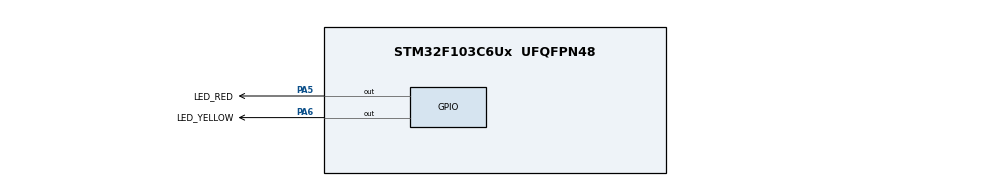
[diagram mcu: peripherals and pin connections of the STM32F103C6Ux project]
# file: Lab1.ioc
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Mcu.Family=STM32F1
Mcu.Name=STM32F103C6Ux
Mcu.Package=UFQFPN48
NVIC.PriorityGroup=NVIC_PRIORITYGROUP_4
PA5.GPIO_Label=LED_RED
PA5.Signal=GPIO_Output
PA6.GPIO_Label=LED_YELLOW
PA6.Signal=GPIO_Output
ProjectManager.HeapSize=0x200
ProjectManager.StackSize=0x400
ProjectManager.TargetToolchain=STM32CubeIDE
RCC.APB1Freq_Value=8000000
RCC.APB2Freq_Value=8000000
VP_SYS_VS_ND.Mode=No_Debug
board=custom

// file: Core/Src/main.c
/* USER CODE BEGIN Header */
/**
  ******************************************************************************
  * @file           : main.c
  * @brief          : Main program body
  ******************************************************************************
  * @attention
  *
  * <h2><center>&copy; Copyright (c) 2023 STMicroelectronics.
  * All rights reserved.</center></h2>
  *
  * This software component is licensed by ST under BSD 3-Clause license,
  * the "License"; You may not use this file except in compliance with the
  * License. You may obtain a copy of the License at:
  *                        opensource.org/licenses/BSD-3-Clause
  *
  ******************************************************************************
  */
/* USER CODE END Header */
#include "main.h"

void SystemClock_Config(void);
static void MX_GPIO_Init(void);

/* USER CODE BEGIN 0 */
void setNumberOnClock(int num){
	switch(num){
	case 0:
		HAL_GPIO_WritePin(LED_0_GPIO_Port, LED_0_Pin, RESET);
	  	break;
	case 1:
		HAL_GPIO_WritePin(LED_1_GPIO_Port, LED_1_Pin, RESET);
		break;
	case 2:
		HAL_GPIO_WritePin(LED_2_GPIO_Port, LED_2_Pin, RESET);
		break;
	case 3:
		HAL_GPIO_WritePin(LED_3_GPIO_Port, LED_3_Pin, RESET);
		break;
	case 4:
		HAL_GPIO_WritePin(LED_4_GPIO_Port, LED_4_Pin, RESET);
		break;
	case 5:
		HAL_GPIO_WritePin(LED_5_GPIO_Port, LED_5_Pin, RESET);
		break;
	case 6:
		HAL_GPIO_WritePin(LED_6_GPIO_Port, LED_6_Pin, RESET);
		break;
	case 7:
		HAL_GPIO_WritePin(LED_7_GPIO_Port, LED_7_Pin, RESET);
		break;
	case 8:
		HAL_GPIO_WritePin(LED_8_GPIO_Port, LED_8_Pin, RESET);
		break;
	case 9:
		HAL_GPIO_WritePin(LED_9_GPIO_Port, LED_9_Pin, RESET);
		break;
	case 10:
		HAL_GPIO_WritePin(LED_10_GPIO_Port, LED_10_Pin, RESET);
		break;
	case 11:
		HAL_GPIO_WritePin(LED_11_GPIO_Port, LED_11_Pin, RESET);
		break;
	default:
		break;

	}
}

void clearAllClock (){
	HAL_GPIO_WritePin(LED_0_GPIO_Port, LED_0_Pin, SET);
	HAL_GPIO_WritePin(LED_1_GPIO_Port, LED_1_Pin, SET);
	HAL_GPIO_WritePin(LED_2_GPIO_Port, LED_2_Pin, SET);
	HAL_GPIO_WritePin(LED_3_GPIO_Port, LED_3_Pin, SET);
	HAL_GPIO_WritePin(LED_4_GPIO_Port, LED_4_Pin, SET);
	HAL_GPIO_WritePin(LED_5_GPIO_Port, LED_5_Pin, SET);
	HAL_GPIO_WritePin(LED_6_GPIO_Port, LED_6_Pin, SET);
	HAL_GPIO_WritePin(LED_7_GPIO_Port, LED_7_Pin, SET);
	HAL_GPIO_WritePin(LED_8_GPIO_Port, LED_8_Pin, SET);
	HAL_GPIO_WritePin(LED_9_GPIO_Port, LED_9_Pin, SET);
	HAL_GPIO_WritePin(LED_10_GPIO_Port, LED_10_Pin, SET);
	HAL_GPIO_WritePin(LED_11_GPIO_Port, LED_11_Pin, SET);
}

void clearNumberOnClock(int num){
	switch(num){
	case 0:
		HAL_GPIO_WritePin(LED_0_GPIO_Port, LED_0_Pin, SET);
		break;
	case 1:
		HAL_GPIO_WritePin(LED_1_GPIO_Port, LED_1_Pin, SET);
		break;
	case 2:
		HAL_GPIO_WritePin(LED_2_GPIO_Port, LED_2_Pin, SET);
		break;
	case 3:
		HAL_GPIO_WritePin(LED_3_GPIO_Port, LED_3_Pin, SET);
		break;
	case 4:
		HAL_GPIO_WritePin(LED_4_GPIO_Port, LED_4_Pin, SET);
		break;
	case 5:
		HAL_GPIO_WritePin(LED_5_GPIO_Port, LED_5_Pin, SET);
		break;
	case 6:
		HAL_GPIO_WritePin(LED_6_GPIO_Port, LED_6_Pin, SET);
		break;
	case 7:
		HAL_GPIO_WritePin(LED_7_GPIO_Port, LED_7_Pin, SET);
		break;
	case 8:
		HAL_GPIO_WritePin(LED_8_GPIO_Port, LED_8_Pin, SET);
		break;
	case 9:
		HAL_GPIO_WritePin(LED_9_GPIO_Port, LED_9_Pin, SET);
		break;
	case 10:
		HAL_GPIO_WritePin(LED_10_GPIO_Port, LED_10_Pin, SET);
		break;
	case 11:
		HAL_GPIO_WritePin(LED_11_GPIO_Port, LED_11_Pin, SET);
		break;
	default:
		break;
	}
}

const int HOUR = 12;
const int MINUTE = 60;
const int SECOND = 60;
/* USER CODE END 0 */

int main(void)
{

  /* MCU Configuration--------------------------------------------------------*/

  /* Reset of all peripherals, Initializes the Flash interface and the Systick. */
  HAL_Init();

  /* Configure the system clock */
  SystemClock_Config();

  /* Initialize all configured peripherals */
  MX_GPIO_Init();

  /* Infinite loop */
  /* USER CODE BEGIN WHILE */
  int sec = 0;
  int min = 0;
  int hour = 0;

  while (1)
  {
	  clearAllClock();
	  if (sec >= SECOND){
		  min++;
		  sec = 0;
	  }

	  if (min >= MINUTE) {
		  hour++;
		  min = 0;
	  }

	  if (hour >= HOUR){
		  hour = 0;
	  }
	  setNumberOnClock(hour);
	  setNumberOnClock(min/5);
	  setNumberOnClock(sec/5);
	  sec++;

	  HAL_Delay(1000);
    /* USER CODE END WHILE */

  }
}

void SystemClock_Config(void)
{
  RCC_OscInitTypeDef RCC_OscInitStruct = {0};
  RCC_ClkInitTypeDef RCC_ClkInitStruct = {0};

  /** Initializes the RCC Oscillators according to the specified parameters
  * in the RCC_OscInitTypeDef structure.
  */
  RCC_OscInitStruct.OscillatorType = RCC_OSCILLATORTYPE_HSI;
  RCC_OscInitStruct.HSIState = RCC_HSI_ON;
  RCC_OscInitStruct.HSICalibrationValue = RCC_HSICALIBRATION_DEFAULT;
  RCC_OscInitStruct.PLL.PLLState = RCC_PLL_NONE;
  if (HAL_RCC_OscConfig(&RCC_OscInitStruct) != HAL_OK)
  {
    Error_Handler();
  }
  /** Initializes the CPU, AHB and APB buses clocks
  */
  RCC_ClkInitStruct.ClockType = RCC_CLOCKTYPE_HCLK|RCC_CLOCKTYPE_SYSCLK
                              |RCC_CLOCKTYPE_PCLK1|RCC_CLOCKTYPE_PCLK2;
  RCC_ClkInitStruct.SYSCLKSource = RCC_SYSCLKSOURCE_HSI;
  RCC_ClkInitStruct.AHBCLKDivider = RCC_SYSCLK_DIV1;
  RCC_ClkInitStruct.APB1CLKDivider = RCC_HCLK_DIV1;
  RCC_ClkInitStruct.APB2CLKDivider = RCC_HCLK_DIV1;

  if (HAL_RCC_ClockConfig(&RCC_ClkInitStruct, FLASH_LATENCY_0) != HAL_OK)
  {
    Error_Handler();
  }
}

static void MX_GPIO_Init(void)
{
  GPIO_InitTypeDef GPIO_InitStruct = {0};

  /* GPIO Ports Clock Enable */
  __HAL_RCC_GPIOA_CLK_ENABLE();

  /*Configure GPIO pin Output Level */
  HAL_GPIO_WritePin(GPIOA, LED_0_Pin|LED_1_Pin|LED_2_Pin|LED_3_Pin
                          |LED_4_Pin|LED_5_Pin|LED_6_Pin|LED_7_Pin
                          |LED_8_Pin|LED_9_Pin|LED_10_Pin|LED_11_Pin, GPIO_PIN_RESET);

  /*Configure GPIO pins : LED_0_Pin LED_1_Pin LED_2_Pin LED_3_Pin
                           LED_4_Pin LED_5_Pin LED_6_Pin LED_7_Pin
                           LED_8_Pin LED_9_Pin LED_10_Pin LED_11_Pin */
  GPIO_InitStruct.Pin = LED_0_Pin|LED_1_Pin|LED_2_Pin|LED_3_Pin
                          |LED_4_Pin|LED_5_Pin|LED_6_Pin|LED_7_Pin
                          |LED_8_Pin|LED_9_Pin|LED_10_Pin|LED_11_Pin;
  GPIO_InitStruct.Mode = GPIO_MODE_OUTPUT_PP;
  GPIO_InitStruct.Pull = GPIO_NOPULL;
  GPIO_InitStruct.Speed = GPIO_SPEED_FREQ_LOW;
  HAL_GPIO_Init(GPIOA, &GPIO_InitStruct);

}

void Error_Handler(void)
{
  __disable_irq();
  while (1)
  {
  }
}

/************************ (C) COPYRIGHT STMicroelectronics *****END OF FILE****/
